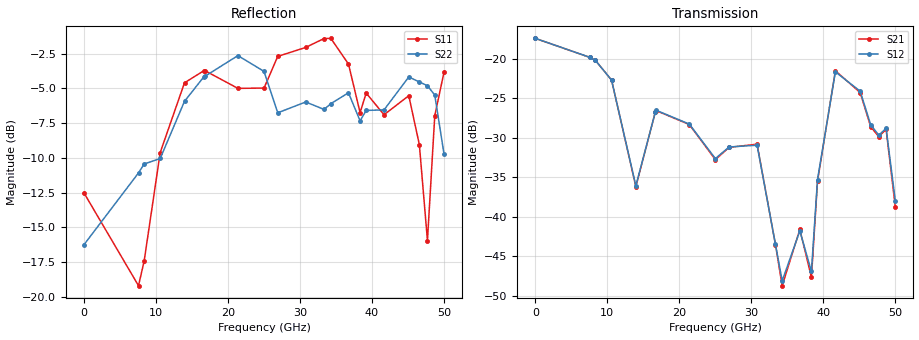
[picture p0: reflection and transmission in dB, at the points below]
!Keysight Technologies,N5245B,MY58422270,A.16.20.02
!Date: Thursday, March 05, 2026 01:17:58
!Correction: S11(C  2-Port  )
!S21(C  2-Port  )
!S12(C  2-Port  )
!S22(C  2-Port  )
!S2P File: Measurements: S11, S21, S12, S22:
# Hz S  dB  R 50
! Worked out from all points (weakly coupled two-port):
!   3201 points, 10 MHz to 50 GHz, reference 50 ohm
!   highest |S21| = -17.46 dB at 10 MHz (marker M1); lowest = -48.7 dB at 34.28 GHz (marker M2)
!   lowest |S11| = -19.2 dB at 7.571 GHz (marker M3), VSWR 1.25, Z = 40.2 - j1.45 ohm
!   |S11| at or under -10 dB: start of sweep to 10.42 GHz; 46.73 GHz to 48.26 GHz (1.521 GHz wide, 3.2 % of centre)
!   |S22| runs from -21.2 to -2.5 dB; largest |S21 - S12| = 0.0037
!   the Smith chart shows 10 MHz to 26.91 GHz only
!   S11 on the Smith chart (normalised r, x): 10 MHz: 1.62, -0.04; 10.59 GHz: 0.53, +0.20; 13.96 GHz: 1.27, +1.62; 16.8 GHz: 1.13, -1.82; 21.38 GHz: 0.31, -0.33; 26.91 GHz: 0.17, +0.36
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1e7  -12.53 -2.5  -17.46 1.8  -17.45 3.3  -16.24 44.1
7.570988e9  -19.20 -170.7  -19.86 42.9  -19.85 42.9  -11.08 -163.7
8.352081e9  -17.44 -164.0  -20.24 8.3  -20.25 8.3  -10.44 178.2
1.058601e10  -9.61 149.8  -22.73 -88.9  -22.73 -89.2  -10.04 105.5
1.396033e10  -4.59 45.0  -36.21 -153.2  -36.10 -153.5  -5.92 -61.0
1.667854e10  -3.71 -41.7  -26.73 159.2  -26.72 159.4  -4.14 -143.8
1.680352e10  -3.72 -45.3  -26.60 154.5  -26.56 154.6  -4.12 -146.1
2.138072e10  -4.99 -140.2  -28.35 14.2  -28.29 14.0  -2.63 133.2
2.5005e10  -4.97 174.5  -32.79 -67.3  -32.66 -66.9  -3.77 70.8
2.691087e10  -2.69 139.7  -31.24 -108.0  -31.19 -108.9  -6.75 37.7
3.080072e10  -2.04 76.6  -30.84 115.0  -30.97 114.3  -5.97 -59.5
3.334708e10  -1.40 35.6  -43.53 -3.4  -43.50 -1.0  -6.51 -131.7
3.428439e10  -1.39 19.4  -48.74 -88.3  -48.13 -89.2  -6.09 -152.3
3.673703e10  -3.24 -32.3  -41.63 105.1  -41.81 99.6  -5.31 159.5
3.834608e10  -6.74 -21.7  -47.68 82.0  -46.94 80.3  -7.33 135.6
3.918966e10  -5.33 -33.1  -35.54 92.4  -35.32 93.4  -6.58 136.1
4.167354e10  -6.89 -55.3  -21.55 -55.3  -21.69 -55.3  -6.54 111.3
4.511035e10  -5.52 -101.7  -24.30 86.7  -24.13 86.6  -4.17 74.3
4.657881e10  -9.04 -153.2  -28.63 31.4  -28.38 32.4  -4.53 53.9
4.770358e10  -15.95 72.7  -29.88 -17.1  -29.69 -17.1  -4.80 41.2
4.871901e10  -6.96 -25.3  -28.95 -88.1  -28.83 -87.0  -5.47 21.0
5e10  -3.84 -72.7  -38.82 -135.4  -38.03 -152.1  -9.70 8.0
